VERSION 5.8 ;
BUSBITCHARS "[]" ;
DIVIDERCHAR "/" ;
UNITS
    DATABASE MICRONS 1000 ;
END UNITS

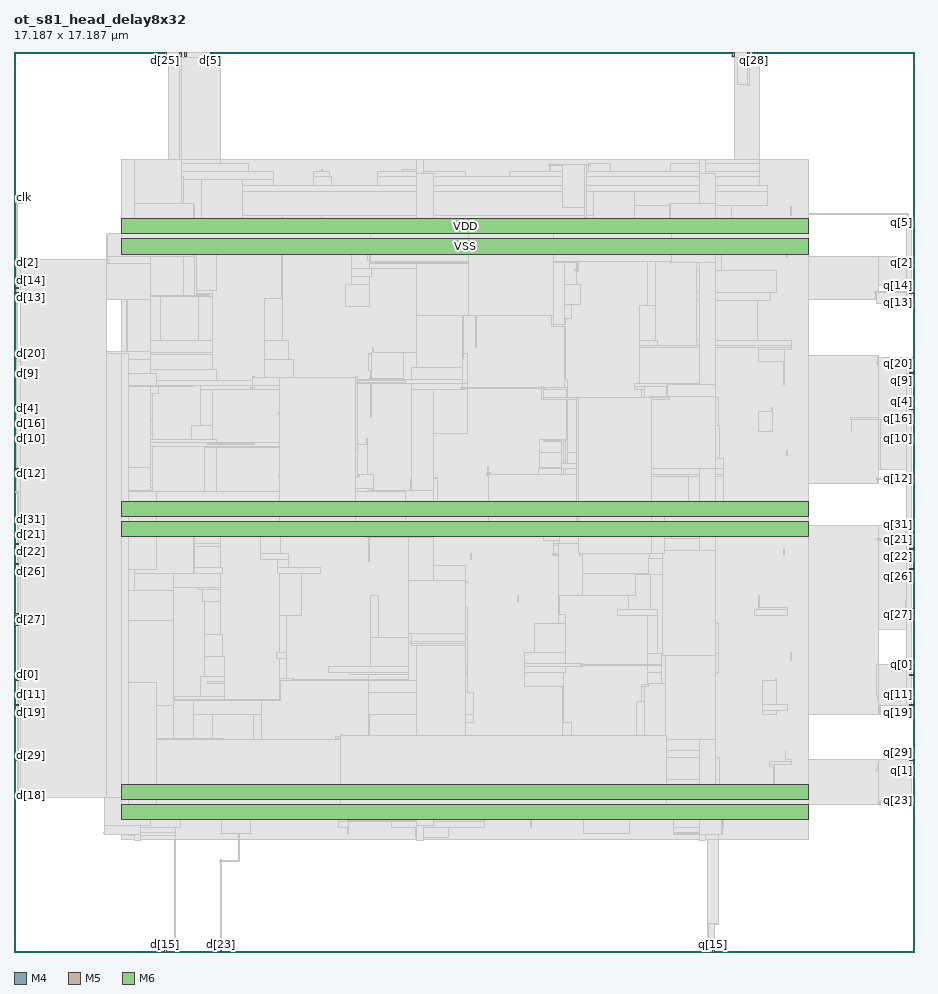
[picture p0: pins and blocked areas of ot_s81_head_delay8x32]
MACRO ot_s81_head_delay8x32
  FOREIGN ot_s81_head_delay8x32 0 0 ;
  CLASS BLOCK ;
  SIZE 17.187 BY 17.187 ;
  PIN clk
    DIRECTION INPUT ;
    USE SIGNAL ;
    PORT
      LAYER M4 ;
        RECT  0 14.4 0.084 14.424 ;
    END
  END clk
  PIN d[0]
    DIRECTION INPUT ;
    USE SIGNAL ;
    PORT
      LAYER M4 ;
        RECT  0 5.28 0.084 5.304 ;
    END
  END d[0]
  PIN d[10]
    DIRECTION INPUT ;
    USE SIGNAL ;
    PORT
      LAYER M4 ;
        RECT  0 9.792 0.084 9.816 ;
    END
  END d[10]
  PIN d[11]
    DIRECTION INPUT ;
    USE SIGNAL ;
    PORT
      LAYER M4 ;
        RECT  0 4.896 0.084 4.92 ;
    END
  END d[11]
  PIN d[12]
    DIRECTION INPUT ;
    USE SIGNAL ;
    PORT
      LAYER M4 ;
        RECT  0 9.12 0.084 9.144 ;
    END
  END d[12]
  PIN d[13]
    DIRECTION INPUT ;
    USE SIGNAL ;
    PORT
      LAYER M4 ;
        RECT  0 12.48 0.084 12.504 ;
    END
  END d[13]
  PIN d[14]
    DIRECTION INPUT ;
    USE SIGNAL ;
    PORT
      LAYER M4 ;
        RECT  0 12.672 0.084 12.696 ;
    END
  END d[14]
  PIN d[15]
    DIRECTION INPUT ;
    USE SIGNAL ;
    PORT
      LAYER M5 ;
        RECT  2.88 0 2.904 0.084 ;
    END
  END d[15]
  PIN d[16]
    DIRECTION INPUT ;
    USE SIGNAL ;
    PORT
      LAYER M4 ;
        RECT  0 10.08 0.084 10.104 ;
    END
  END d[16]
  PIN d[17]
    DIRECTION INPUT ;
    USE SIGNAL ;
    PORT
      LAYER M4 ;
        RECT  0 5.184 0.084 5.208 ;
    END
  END d[17]
  PIN d[18]
    DIRECTION INPUT ;
    USE SIGNAL ;
    PORT
      LAYER M4 ;
        RECT  0 2.976 0.084 3 ;
    END
  END d[18]
  PIN d[19]
    DIRECTION INPUT ;
    USE SIGNAL ;
    PORT
      LAYER M4 ;
        RECT  0 4.704 0.084 4.728 ;
    END
  END d[19]
  PIN d[1]
    DIRECTION INPUT ;
    USE SIGNAL ;
    PORT
      LAYER M4 ;
        RECT  0 3.648 0.084 3.672 ;
    END
  END d[1]
  PIN d[20]
    DIRECTION INPUT ;
    USE SIGNAL ;
    PORT
      LAYER M4 ;
        RECT  0 11.424 0.084 11.448 ;
    END
  END d[20]
  PIN d[21]
    DIRECTION INPUT ;
    USE SIGNAL ;
    PORT
      LAYER M4 ;
        RECT  0 7.968 0.084 7.992 ;
    END
  END d[21]
  PIN d[22]
    DIRECTION INPUT ;
    USE SIGNAL ;
    PORT
      LAYER M4 ;
        RECT  0 7.776 0.084 7.8 ;
    END
  END d[22]
  PIN d[23]
    DIRECTION INPUT ;
    USE SIGNAL ;
    PORT
      LAYER M5 ;
        RECT  3.936 0 3.96 0.084 ;
    END
  END d[23]
  PIN d[24]
    DIRECTION INPUT ;
    USE SIGNAL ;
    PORT
      LAYER M4 ;
        RECT  0 11.328 0.084 11.352 ;
    END
  END d[24]
  PIN d[25]
    DIRECTION INPUT ;
    USE SIGNAL ;
    PORT
      LAYER M5 ;
        RECT  2.88 17.103 2.904 17.187 ;
    END
  END d[25]
  PIN d[26]
    DIRECTION INPUT ;
    USE SIGNAL ;
    PORT
      LAYER M4 ;
        RECT  0 7.392 0.084 7.416 ;
    END
  END d[26]
  PIN d[27]
    DIRECTION INPUT ;
    USE SIGNAL ;
    PORT
      LAYER M4 ;
        RECT  0 6.336 0.084 6.36 ;
    END
  END d[27]
  PIN d[28]
    DIRECTION INPUT ;
    USE SIGNAL ;
    PORT
      LAYER M5 ;
        RECT  3.264 17.103 3.288 17.187 ;
    END
  END d[28]
  PIN d[29]
    DIRECTION INPUT ;
    USE SIGNAL ;
    PORT
      LAYER M4 ;
        RECT  0 3.744 0.084 3.768 ;
    END
  END d[29]
  PIN d[2]
    DIRECTION INPUT ;
    USE SIGNAL ;
    PORT
      LAYER M4 ;
        RECT  0 13.152 0.084 13.176 ;
    END
  END d[2]
  PIN d[30]
    DIRECTION INPUT ;
    USE SIGNAL ;
    PORT
      LAYER M5 ;
        RECT  3.168 17.103 3.192 17.187 ;
    END
  END d[30]
  PIN d[31]
    DIRECTION INPUT ;
    USE SIGNAL ;
    PORT
      LAYER M4 ;
        RECT  0 8.256 0.084 8.28 ;
    END
  END d[31]
  PIN d[3]
    DIRECTION INPUT ;
    USE SIGNAL ;
    PORT
      LAYER M4 ;
        RECT  0 6.432 0.084 6.456 ;
    END
  END d[3]
  PIN d[4]
    DIRECTION INPUT ;
    USE SIGNAL ;
    PORT
      LAYER M4 ;
        RECT  0 10.368 0.084 10.392 ;
    END
  END d[4]
  PIN d[5]
    DIRECTION INPUT ;
    USE SIGNAL ;
    PORT
      LAYER M5 ;
        RECT  3.744 17.103 3.768 17.187 ;
    END
  END d[5]
  PIN d[6]
    DIRECTION INPUT ;
    USE SIGNAL ;
    PORT
      LAYER M4 ;
        RECT  0 12.576 0.084 12.6 ;
    END
  END d[6]
  PIN d[7]
    DIRECTION INPUT ;
    USE SIGNAL ;
    PORT
      LAYER M4 ;
        RECT  0 9.216 0.084 9.24 ;
    END
  END d[7]
  PIN d[8]
    DIRECTION INPUT ;
    USE SIGNAL ;
    PORT
      LAYER M4 ;
        RECT  0 6.24 0.084 6.264 ;
    END
  END d[8]
  PIN d[9]
    DIRECTION INPUT ;
    USE SIGNAL ;
    PORT
      LAYER M4 ;
        RECT  0 11.04 0.084 11.064 ;
    END
  END d[9]
  PIN q[0]
    DIRECTION OUTPUT ;
    USE SIGNAL ;
    PORT
      LAYER M4 ;
        RECT  17.103 5.472 17.187 5.496 ;
    END
  END q[0]
  PIN q[10]
    DIRECTION OUTPUT ;
    USE SIGNAL ;
    PORT
      LAYER M4 ;
        RECT  17.103 9.792 17.187 9.816 ;
    END
  END q[10]
  PIN q[11]
    DIRECTION OUTPUT ;
    USE SIGNAL ;
    PORT
      LAYER M4 ;
        RECT  17.103 4.896 17.187 4.92 ;
    END
  END q[11]
  PIN q[12]
    DIRECTION OUTPUT ;
    USE SIGNAL ;
    PORT
      LAYER M4 ;
        RECT  17.103 9.024 17.187 9.048 ;
    END
  END q[12]
  PIN q[13]
    DIRECTION OUTPUT ;
    USE SIGNAL ;
    PORT
      LAYER M4 ;
        RECT  17.103 12.384 17.187 12.408 ;
    END
  END q[13]
  PIN q[14]
    DIRECTION OUTPUT ;
    USE SIGNAL ;
    PORT
      LAYER M4 ;
        RECT  17.103 12.576 17.187 12.6 ;
    END
  END q[14]
  PIN q[15]
    DIRECTION OUTPUT ;
    USE SIGNAL ;
    PORT
      LAYER M5 ;
        RECT  13.344 0 13.368 0.084 ;
    END
  END q[15]
  PIN q[16]
    DIRECTION OUTPUT ;
    USE SIGNAL ;
    PORT
      LAYER M4 ;
        RECT  17.103 10.176 17.187 10.2 ;
    END
  END q[16]
  PIN q[17]
    DIRECTION OUTPUT ;
    USE SIGNAL ;
    PORT
      LAYER M4 ;
        RECT  17.103 5.28 17.187 5.304 ;
    END
  END q[17]
  PIN q[18]
    DIRECTION OUTPUT ;
    USE SIGNAL ;
    PORT
      LAYER M5 ;
        RECT  13.248 0 13.272 0.084 ;
    END
  END q[18]
  PIN q[19]
    DIRECTION OUTPUT ;
    USE SIGNAL ;
    PORT
      LAYER M4 ;
        RECT  17.103 4.704 17.187 4.728 ;
    END
  END q[19]
  PIN q[1]
    DIRECTION OUTPUT ;
    USE SIGNAL ;
    PORT
      LAYER M4 ;
        RECT  17.103 3.456 17.187 3.48 ;
    END
  END q[1]
  PIN q[20]
    DIRECTION OUTPUT ;
    USE SIGNAL ;
    PORT
      LAYER M4 ;
        RECT  17.103 11.232 17.187 11.256 ;
    END
  END q[20]
  PIN q[21]
    DIRECTION OUTPUT ;
    USE SIGNAL ;
    PORT
      LAYER M4 ;
        RECT  17.103 7.872 17.187 7.896 ;
    END
  END q[21]
  PIN q[22]
    DIRECTION OUTPUT ;
    USE SIGNAL ;
    PORT
      LAYER M4 ;
        RECT  17.103 7.68 17.187 7.704 ;
    END
  END q[22]
  PIN q[23]
    DIRECTION OUTPUT ;
    USE SIGNAL ;
    PORT
      LAYER M4 ;
        RECT  17.103 2.88 17.187 2.904 ;
    END
  END q[23]
  PIN q[24]
    DIRECTION OUTPUT ;
    USE SIGNAL ;
    PORT
      LAYER M4 ;
        RECT  17.103 11.328 17.187 11.352 ;
    END
  END q[24]
  PIN q[25]
    DIRECTION OUTPUT ;
    USE SIGNAL ;
    PORT
      LAYER M5 ;
        RECT  13.728 17.103 13.752 17.187 ;
    END
  END q[25]
  PIN q[26]
    DIRECTION OUTPUT ;
    USE SIGNAL ;
    PORT
      LAYER M4 ;
        RECT  17.103 7.296 17.187 7.32 ;
    END
  END q[26]
  PIN q[27]
    DIRECTION OUTPUT ;
    USE SIGNAL ;
    PORT
      LAYER M4 ;
        RECT  17.103 6.432 17.187 6.456 ;
    END
  END q[27]
  PIN q[28]
    DIRECTION OUTPUT ;
    USE SIGNAL ;
    PORT
      LAYER M5 ;
        RECT  14.112 17.103 14.136 17.187 ;
    END
  END q[28]
  PIN q[29]
    DIRECTION OUTPUT ;
    USE SIGNAL ;
    PORT
      LAYER M4 ;
        RECT  17.103 3.648 17.187 3.672 ;
    END
  END q[29]
  PIN q[2]
    DIRECTION OUTPUT ;
    USE SIGNAL ;
    PORT
      LAYER M4 ;
        RECT  17.103 13.152 17.187 13.176 ;
    END
  END q[2]
  PIN q[30]
    DIRECTION OUTPUT ;
    USE SIGNAL ;
    PORT
      LAYER M5 ;
        RECT  14.016 17.103 14.04 17.187 ;
    END
  END q[30]
  PIN q[31]
    DIRECTION OUTPUT ;
    USE SIGNAL ;
    PORT
      LAYER M4 ;
        RECT  17.103 8.16 17.187 8.184 ;
    END
  END q[31]
  PIN q[3]
    DIRECTION OUTPUT ;
    USE SIGNAL ;
    PORT
      LAYER M4 ;
        RECT  17.103 6.528 17.187 6.552 ;
    END
  END q[3]
  PIN q[4]
    DIRECTION OUTPUT ;
    USE SIGNAL ;
    PORT
      LAYER M4 ;
        RECT  17.103 10.368 17.187 10.392 ;
    END
  END q[4]
  PIN q[5]
    DIRECTION OUTPUT ;
    USE SIGNAL ;
    PORT
      LAYER M4 ;
        RECT  17.103 13.92 17.187 13.944 ;
    END
  END q[5]
  PIN q[6]
    DIRECTION OUTPUT ;
    USE SIGNAL ;
    PORT
      LAYER M4 ;
        RECT  17.103 12.48 17.187 12.504 ;
    END
  END q[6]
  PIN q[7]
    DIRECTION OUTPUT ;
    USE SIGNAL ;
    PORT
      LAYER M4 ;
        RECT  17.103 9.12 17.187 9.144 ;
    END
  END q[7]
  PIN q[8]
    DIRECTION OUTPUT ;
    USE SIGNAL ;
    PORT
      LAYER M4 ;
        RECT  17.103 6.336 17.187 6.36 ;
    END
  END q[8]
  PIN q[9]
    DIRECTION OUTPUT ;
    USE SIGNAL ;
    PORT
      LAYER M4 ;
        RECT  17.103 11.04 17.187 11.064 ;
    END
  END q[9]
  PIN VDD
    DIRECTION INOUT ;
    USE POWER ;
    PORT
      LAYER M6 ;
        RECT  2.052 13.713 15.174 14.001 ;
        RECT  2.052 8.313 15.174 8.601 ;
        RECT  2.052 2.913 15.174 3.201 ;
    END
  END VDD
  PIN VSS
    DIRECTION INOUT ;
    USE GROUND ;
    PORT
      LAYER M6 ;
        RECT  2.052 13.329 15.174 13.617 ;
        RECT  2.052 7.929 15.174 8.217 ;
        RECT  2.052 2.529 15.174 2.817 ;
    END
  END VSS
  OBS
    LAYER RVTN ;
     RECT  2.052 2.16 15.174 2.295 ;
     RECT  2.052 2.565 15.174 2.835 ;
     RECT  2.052 3.105 15.174 3.375 ;
     RECT  2.052 3.645 15.174 3.915 ;
     RECT  2.052 4.185 15.174 4.455 ;
     RECT  2.052 4.725 15.174 4.995 ;
     RECT  2.052 5.265 15.174 5.535 ;
     RECT  2.052 5.805 15.174 6.075 ;
     RECT  2.052 6.345 15.174 6.615 ;
     RECT  2.052 6.885 15.174 7.155 ;
     RECT  2.052 7.425 15.174 7.695 ;
     RECT  2.052 7.965 15.174 8.235 ;
     RECT  2.052 8.505 15.174 8.775 ;
     RECT  2.052 9.045 15.174 9.315 ;
     RECT  2.052 9.585 15.174 9.855 ;
     RECT  2.052 10.125 15.174 10.395 ;
     RECT  2.052 10.665 15.174 10.935 ;
     RECT  2.052 11.205 15.174 11.475 ;
     RECT  2.052 11.745 15.174 12.015 ;
     RECT  2.052 12.285 15.174 12.555 ;
     RECT  2.052 12.825 15.174 13.095 ;
     RECT  2.052 13.365 15.174 13.635 ;
     RECT  2.052 13.905 15.174 14.175 ;
     RECT  2.052 14.445 15.174 14.715 ;
     RECT  2.052 14.985 15.174 15.12 ;
    LAYER RVTP ;
     RECT  2.052 2.295 15.174 2.565 ;
     RECT  2.052 2.835 15.174 3.105 ;
     RECT  2.052 3.375 15.174 3.645 ;
     RECT  2.052 3.915 15.174 4.185 ;
     RECT  2.052 4.455 15.174 4.725 ;
     RECT  2.052 4.995 15.174 5.265 ;
     RECT  2.052 5.535 15.174 5.805 ;
     RECT  2.052 6.075 15.174 6.345 ;
     RECT  2.052 6.615 15.174 6.885 ;
     RECT  2.052 7.155 15.174 7.425 ;
     RECT  2.052 7.695 15.174 7.965 ;
     RECT  2.052 8.235 15.174 8.505 ;
     RECT  2.052 8.775 15.174 9.045 ;
     RECT  2.052 9.315 15.174 9.585 ;
     RECT  2.052 9.855 15.174 10.125 ;
     RECT  2.052 10.395 15.174 10.665 ;
     RECT  2.052 10.935 15.174 11.205 ;
     RECT  2.052 11.475 15.174 11.745 ;
     RECT  2.052 12.015 15.174 12.285 ;
     RECT  2.052 12.555 15.174 12.825 ;
     RECT  2.052 13.095 15.174 13.365 ;
     RECT  2.052 13.635 15.174 13.905 ;
     RECT  2.052 14.175 15.174 14.445 ;
     RECT  2.052 14.715 15.174 14.985 ;
    LAYER M1 ;
     RECT  2.052 2.151 15.174 15.129 ;
    LAYER M2 ;
     RECT  1.147 8.172 1.687 8.19 ;
     RECT  1.687 5.85 2.052 5.868 ;
     RECT  1.687 7.74 2.052 8.19 ;
     RECT  1.147 9.792 2.052 9.81 ;
     RECT  1.759 11.412 2.052 11.43 ;
     RECT  1.147 13.032 2.052 13.05 ;
     RECT  2.052 2.151 15.174 15.129 ;
     RECT  15.174 2.808 16.511 3.672 ;
     RECT  15.174 4.536 16.511 8.154 ;
     RECT  15.174 8.946 16.511 11.394 ;
     RECT  15.174 12.456 16.511 13.284 ;
     RECT  16.511 2.808 16.547 2.826 ;
     RECT  16.511 3.654 16.547 3.672 ;
     RECT  16.511 4.536 16.547 5.184 ;
     RECT  16.511 9.216 16.547 11.304 ;
     RECT  16.511 6.156 17.087 8.154 ;
     RECT  16.547 9.216 17.087 10.314 ;
     RECT  16.511 12.726 17.087 13.284 ;
     RECT  15.174 14.076 17.087 14.094 ;
    LAYER M3 ;
     RECT  13.248 0.091 13.266 0.523 ;
     RECT  3.06 0.091 3.078 2.143 ;
     RECT  13.248 0.523 13.446 2.143 ;
     RECT  7.707 2.143 7.797 2.191 ;
     RECT  2.307 2.143 3.078 2.227 ;
     RECT  13.107 2.143 13.446 2.251 ;
     RECT  4.284 1.723 4.302 2.263 ;
     RECT  2.196 2.227 3.078 2.285 ;
     RECT  2.307 2.285 3.078 2.371 ;
     RECT  6.372 2.263 6.39 2.371 ;
     RECT  7.668 2.191 8.298 2.371 ;
     RECT  12.6 2.251 13.446 2.371 ;
     RECT  6.192 2.371 6.39 2.491 ;
     RECT  7.2 2.371 8.982 2.491 ;
     RECT  2.307 2.371 3.186 2.641 ;
     RECT  3.96 2.263 4.518 2.641 ;
     RECT  5.292 2.605 5.31 2.641 ;
     RECT  6.192 2.491 8.982 2.641 ;
     RECT  10.872 2.263 11.754 2.641 ;
     RECT  12.6 2.371 13.554 2.641 ;
     RECT  2.307 2.641 8.982 2.731 ;
     RECT  9.864 2.371 9.882 2.731 ;
     RECT  2.307 2.731 9.882 2.759 ;
     RECT  14.688 2.731 14.706 2.795 ;
     RECT  10.656 2.641 13.554 2.909 ;
     RECT  16.524 2.803 16.542 2.909 ;
     RECT  10.656 2.909 10.674 2.911 ;
     RECT  11.484 2.909 13.554 2.911 ;
     RECT  2.307 2.759 6.894 3.029 ;
     RECT  7.668 2.759 9.378 3.029 ;
     RECT  10.188 2.911 10.674 3.029 ;
     RECT  11.484 2.911 13.662 3.029 ;
     RECT  7.707 3.029 9.234 3.065 ;
     RECT  6.732 3.029 6.786 3.173 ;
     RECT  2.307 3.029 5.814 3.299 ;
     RECT  11.484 3.029 13.482 3.299 ;
     RECT  2.307 3.299 5.634 3.307 ;
     RECT  2.196 3.307 5.634 3.437 ;
     RECT  14.508 2.911 14.526 3.541 ;
     RECT  16.488 3.451 16.506 3.569 ;
     RECT  14.436 3.541 14.526 3.577 ;
     RECT  14.436 3.577 14.85 3.641 ;
     RECT  14.724 3.641 14.85 3.677 ;
     RECT  16.524 3.643 16.542 3.683 ;
     RECT  11.556 3.299 13.482 3.713 ;
     RECT  2.268 3.437 5.634 3.773 ;
     RECT  4.572 3.773 5.634 3.839 ;
     RECT  11.556 3.713 13.389 3.839 ;
     RECT  14.724 3.677 14.742 3.839 ;
     RECT  5.616 3.839 5.634 3.911 ;
     RECT  2.268 3.773 3.798 4.019 ;
     RECT  6.768 3.173 6.786 4.075 ;
     RECT  10.476 3.029 10.638 4.075 ;
     RECT  6.192 4.075 6.786 4.115 ;
     RECT  10.116 4.075 10.638 4.115 ;
     RECT  11.88 3.839 13.389 4.115 ;
     RECT  2.268 4.019 2.682 4.225 ;
     RECT  10.476 4.115 10.638 4.379 ;
     RECT  7.707 3.065 8.622 4.387 ;
     RECT  3.42 4.019 3.798 4.531 ;
     RECT  4.572 3.839 4.734 4.531 ;
     RECT  6.768 4.115 6.786 4.531 ;
     RECT  7.707 4.387 8.766 4.531 ;
     RECT  2.196 4.225 2.682 4.541 ;
     RECT  14.292 4.531 14.562 4.621 ;
     RECT  2.268 4.541 2.682 4.685 ;
     RECT  14.292 4.621 14.778 4.721 ;
     RECT  11.88 4.115 12.042 4.793 ;
     RECT  2.304 4.685 2.682 4.801 ;
     RECT  3.42 4.531 4.734 4.801 ;
     RECT  16.524 4.531 16.542 4.801 ;
     RECT  2.304 4.801 5.094 4.829 ;
     RECT  2.304 4.829 4.014 4.877 ;
     RECT  6.768 4.531 8.766 4.955 ;
     RECT  10.476 4.379 10.494 5.071 ;
     RECT  11.988 4.793 12.042 5.071 ;
     RECT  11.988 5.071 12.114 5.099 ;
     RECT  12.096 5.099 12.114 5.131 ;
     RECT  13.032 4.115 13.389 5.131 ;
     RECT  5.076 4.829 5.094 5.179 ;
     RECT  14.292 4.721 14.562 5.189 ;
     RECT  5.076 5.179 5.346 5.225 ;
     RECT  14.544 5.189 14.562 5.225 ;
     RECT  3.564 4.877 4.014 5.261 ;
     RECT  6.768 4.955 8.658 5.305 ;
     RECT  16.488 4.801 16.542 5.309 ;
     RECT  6.408 5.305 8.658 5.341 ;
     RECT  9.756 5.071 10.494 5.341 ;
     RECT  12.096 5.131 13.389 5.341 ;
     RECT  6.012 5.341 8.658 5.459 ;
     RECT  9.756 5.341 10.53 5.461 ;
     RECT  9.756 5.461 10.854 5.501 ;
     RECT  16.488 5.309 16.506 5.501 ;
     RECT  5.076 5.225 5.202 5.611 ;
     RECT  3.636 5.261 4.014 5.639 ;
     RECT  12.096 5.341 13.446 5.693 ;
     RECT  2.304 4.877 2.79 5.729 ;
     RECT  5.004 5.611 5.202 5.729 ;
     RECT  9.756 5.501 10.53 5.729 ;
     RECT  14.832 5.575 14.85 5.729 ;
     RECT  2.304 5.729 2.646 5.845 ;
     RECT  6.804 5.459 8.658 5.999 ;
     RECT  3.636 5.639 3.978 6.071 ;
     RECT  1.692 5.845 2.646 6.269 ;
     RECT  9.936 5.729 10.53 6.269 ;
     RECT  13.104 5.693 13.446 6.269 ;
     RECT  5.076 5.729 5.202 6.421 ;
     RECT  12.096 5.693 12.294 6.421 ;
     RECT  13.104 6.269 13.389 6.421 ;
     RECT  10.404 6.269 10.53 6.449 ;
     RECT  17.064 6.151 17.082 6.523 ;
     RECT  11.52 6.421 12.294 6.539 ;
     RECT  13.068 6.421 13.389 6.539 ;
     RECT  14.148 6.421 14.778 6.539 ;
     RECT  7.707 5.999 8.658 6.575 ;
     RECT  14.22 6.539 14.778 6.575 ;
     RECT  3.636 6.071 3.942 6.691 ;
     RECT  17.028 6.523 17.082 6.719 ;
     RECT  6.804 5.999 6.966 6.809 ;
     RECT  9.612 6.691 9.63 6.809 ;
     RECT  14.22 6.575 14.238 6.809 ;
     RECT  3.6 6.691 3.942 6.925 ;
     RECT  2.196 6.269 2.646 6.961 ;
     RECT  3.528 6.925 3.942 6.961 ;
     RECT  10.404 6.449 10.422 7.195 ;
     RECT  11.736 6.539 12.15 7.229 ;
     RECT  2.196 6.961 3.942 7.231 ;
     RECT  5.076 6.421 5.49 7.231 ;
     RECT  2.196 7.231 3.978 7.349 ;
     RECT  5.04 7.231 5.85 7.349 ;
     RECT  7.707 6.575 8.622 7.385 ;
     RECT  12.132 7.229 12.15 7.435 ;
     RECT  13.107 6.539 13.389 7.435 ;
     RECT  5.04 7.349 5.238 7.501 ;
     RECT  10.404 7.195 10.818 7.579 ;
     RECT  4.716 7.501 5.238 7.619 ;
     RECT  8.712 7.501 8.73 7.619 ;
     RECT  14.688 7.591 14.706 7.691 ;
     RECT  2.196 7.349 3.942 7.735 ;
     RECT  10.296 7.579 10.818 7.765 ;
     RECT  1.692 7.735 3.942 7.805 ;
     RECT  10.296 7.765 10.854 7.805 ;
     RECT  10.296 7.805 10.422 7.861 ;
     RECT  17.064 6.719 17.082 7.861 ;
     RECT  12.132 7.435 13.389 7.889 ;
     RECT  16.488 7.861 17.082 7.901 ;
     RECT  6.768 7.465 6.786 7.949 ;
     RECT  4.716 7.619 5.094 7.963 ;
     RECT  12.564 7.889 13.389 7.963 ;
     RECT  10.116 7.861 10.422 8.159 ;
     RECT  17.064 7.901 17.082 8.189 ;
     RECT  1.152 7.963 1.17 8.195 ;
     RECT  12.564 7.963 13.446 8.195 ;
     RECT  12.888 8.195 13.446 8.311 ;
     RECT  2.307 7.805 3.942 8.429 ;
     RECT  4.68 7.963 5.094 8.429 ;
     RECT  6.048 8.311 6.066 8.429 ;
     RECT  12.888 8.311 13.59 8.429 ;
     RECT  8.928 8.005 8.946 8.465 ;
     RECT  11.808 8.167 11.826 8.465 ;
     RECT  7.707 7.385 7.989 8.522 ;
     RECT  6.84 8.522 7.989 8.539 ;
     RECT  2.307 8.429 2.862 8.699 ;
     RECT  6.84 8.539 8.082 8.699 ;
     RECT  2.307 8.699 2.754 8.735 ;
     RECT  2.307 8.735 2.646 8.743 ;
     RECT  2.232 8.743 2.646 8.815 ;
     RECT  6.84 8.699 6.858 8.851 ;
     RECT  2.196 8.815 2.646 8.861 ;
     RECT  2.232 8.861 2.646 9.005 ;
     RECT  7.707 8.699 8.082 9.053 ;
     RECT  16.488 8.941 16.506 9.053 ;
     RECT  10.404 8.159 10.422 9.067 ;
     RECT  10.404 9.067 10.53 9.085 ;
     RECT  11.988 8.851 12.114 9.085 ;
     RECT  12.888 8.429 13.554 9.085 ;
     RECT  5.112 9.067 5.13 9.113 ;
     RECT  6.516 8.851 6.858 9.113 ;
     RECT  11.988 9.085 13.554 9.113 ;
     RECT  10.008 9.085 10.53 9.239 ;
     RECT  12.024 9.113 13.554 9.239 ;
     RECT  10.044 9.239 10.53 9.247 ;
     RECT  9.036 9.085 9.054 9.275 ;
     RECT  12.924 9.239 13.554 9.419 ;
     RECT  10.044 9.247 10.746 9.545 ;
     RECT  14.76 9.481 14.778 9.581 ;
     RECT  3.636 8.429 3.87 9.625 ;
     RECT  5.076 9.391 5.094 9.625 ;
     RECT  2.307 9.005 2.646 9.661 ;
     RECT  3.636 9.625 5.094 9.661 ;
     RECT  6.516 9.113 6.75 9.689 ;
     RECT  2.307 9.661 5.094 9.725 ;
     RECT  2.307 9.725 3.87 9.779 ;
     RECT  10.044 9.545 10.566 9.779 ;
     RECT  6.732 9.689 6.75 9.815 ;
     RECT  1.152 9.787 1.17 9.824 ;
     RECT  2.307 9.779 2.646 9.895 ;
     RECT  7.707 9.053 7.989 9.895 ;
     RECT  12.024 9.239 12.186 9.965 ;
     RECT  3.384 9.779 3.798 10.049 ;
     RECT  12.924 9.419 13.482 10.049 ;
     RECT  2.304 9.895 2.646 10.165 ;
     RECT  5.076 9.725 5.094 10.201 ;
     RECT  15.984 9.931 16.002 10.205 ;
     RECT  14.22 9.931 14.49 10.319 ;
     RECT  14.472 10.319 14.49 10.391 ;
     RECT  17.064 9.115 17.082 10.397 ;
     RECT  12.024 9.965 12.042 10.471 ;
     RECT  12.924 10.049 13.446 10.589 ;
     RECT  2.196 10.165 2.646 10.669 ;
     RECT  3.564 10.049 3.798 10.741 ;
     RECT  5.076 10.201 5.166 10.741 ;
     RECT  7.707 9.895 8.658 10.741 ;
     RECT  10.548 9.779 10.566 10.741 ;
     RECT  11.988 10.471 12.042 10.741 ;
     RECT  10.116 10.741 10.566 10.781 ;
     RECT  11.844 10.741 12.042 10.795 ;
     RECT  12.924 10.589 13.389 10.795 ;
     RECT  2.196 10.669 2.754 10.831 ;
     RECT  3.564 10.741 5.346 10.831 ;
     RECT  2.196 10.831 5.346 10.859 ;
     RECT  7.668 10.741 8.658 10.859 ;
     RECT  11.844 10.795 13.389 10.859 ;
     RECT  10.512 10.781 10.566 10.931 ;
     RECT  6.804 10.201 6.822 11.101 ;
     RECT  2.196 10.859 3.87 11.129 ;
     RECT  16.524 11.011 16.542 11.227 ;
     RECT  14.688 10.831 14.706 11.281 ;
     RECT  4.788 10.859 5.346 11.309 ;
     RECT  16.488 11.227 16.542 11.357 ;
     RECT  16.488 11.357 16.506 11.399 ;
     RECT  2.196 11.129 3.798 11.407 ;
     RECT  6.768 11.101 6.822 11.407 ;
     RECT  6.768 11.407 6.93 11.435 ;
     RECT  7.707 10.859 8.658 11.435 ;
     RECT  1.764 11.407 3.798 11.453 ;
     RECT  6.84 11.435 6.93 11.453 ;
     RECT  14.22 11.281 14.706 11.515 ;
     RECT  6.84 11.453 6.858 11.543 ;
     RECT  11.952 10.859 13.389 11.551 ;
     RECT  14.22 11.515 14.85 11.551 ;
     RECT  11.952 11.551 14.85 11.579 ;
     RECT  2.232 11.453 3.798 11.669 ;
     RECT  4.788 11.309 5.238 11.669 ;
     RECT  11.952 11.579 12.294 11.669 ;
     RECT  13.032 11.579 14.85 11.669 ;
     RECT  10.512 10.931 10.53 11.947 ;
     RECT  10.44 11.947 10.53 11.984 ;
     RECT  10.512 11.984 10.53 12.091 ;
     RECT  7.707 11.435 8.082 12.187 ;
     RECT  8.82 11.551 8.838 12.187 ;
     RECT  7.707 12.187 8.838 12.325 ;
     RECT  11.952 11.669 12.258 12.353 ;
     RECT  10.512 12.091 10.638 12.361 ;
     RECT  13.032 11.669 14.202 12.451 ;
     RECT  16.488 12.379 16.506 12.475 ;
     RECT  16.488 12.475 17.082 12.478 ;
     RECT  4.788 11.669 5.13 12.479 ;
     RECT  7.707 12.325 8.91 12.479 ;
     RECT  2.232 11.669 2.79 12.523 ;
     RECT  3.528 11.669 3.798 12.523 ;
     RECT  2.232 12.523 3.798 12.571 ;
     RECT  13.032 12.451 14.454 12.595 ;
     RECT  16.452 12.478 17.082 12.605 ;
     RECT  2.196 12.571 3.798 12.631 ;
     RECT  6.336 12.325 6.786 12.749 ;
     RECT  10.512 12.361 10.818 12.749 ;
     RECT  6.444 12.749 6.786 12.901 ;
     RECT  13.032 12.595 14.562 13.019 ;
     RECT  6.444 12.901 6.822 13.051 ;
     RECT  1.152 12.571 1.17 13.055 ;
     RECT  10.512 12.749 10.746 13.171 ;
     RECT  7.707 12.479 8.694 13.333 ;
     RECT  14.76 13.261 14.778 13.361 ;
     RECT  7.707 13.333 8.946 13.405 ;
     RECT  2.196 12.631 3.87 13.441 ;
     RECT  5.112 12.479 5.13 13.441 ;
     RECT  12.096 12.353 12.258 13.441 ;
     RECT  13.032 13.019 13.518 13.441 ;
     RECT  2.196 13.441 5.13 13.559 ;
     RECT  6.444 13.051 6.966 13.639 ;
     RECT  6.264 13.639 6.966 13.711 ;
     RECT  9.936 13.171 10.746 13.711 ;
     RECT  6.012 13.711 6.966 13.819 ;
     RECT  2.196 13.559 3.582 13.865 ;
     RECT  5.868 13.819 6.966 13.963 ;
     RECT  7.707 13.405 9.126 13.963 ;
     RECT  12.096 13.441 13.518 13.963 ;
     RECT  5.868 13.963 9.126 13.981 ;
     RECT  9.936 13.711 10.998 13.981 ;
     RECT  11.988 13.963 13.518 13.981 ;
     RECT  4.356 13.559 5.13 14.071 ;
     RECT  5.868 13.981 11.07 14.071 ;
     RECT  17.064 12.605 17.082 14.099 ;
     RECT  14.832 14.071 14.85 14.243 ;
     RECT  11.844 13.981 13.698 14.251 ;
     RECT  4.356 14.071 11.07 14.521 ;
     RECT  11.844 14.251 14.382 14.521 ;
     RECT  4.356 14.521 14.382 14.639 ;
     RECT  2.307 13.865 3.582 14.755 ;
     RECT  4.356 14.639 4.95 14.755 ;
     RECT  5.724 14.639 6.066 14.819 ;
     RECT  6.948 14.639 14.238 14.819 ;
     RECT  2.307 14.755 4.95 14.909 ;
     RECT  5.724 14.819 6.03 14.909 ;
     RECT  6.948 14.819 8.622 14.909 ;
     RECT  9.468 14.819 14.238 14.909 ;
     RECT  5.868 14.909 5.886 14.945 ;
     RECT  7.416 14.909 7.797 14.945 ;
     RECT  2.307 14.909 4.482 15.053 ;
     RECT  10.224 14.909 10.242 15.053 ;
     RECT  10.98 14.909 11.394 15.053 ;
     RECT  12.528 14.909 14.238 15.053 ;
     RECT  10.98 15.053 10.998 15.059 ;
     RECT  2.307 15.053 3.942 15.137 ;
     RECT  7.707 14.945 7.797 15.137 ;
     RECT  13.107 15.053 14.238 15.137 ;
     RECT  2.952 15.137 3.942 17.117 ;
     RECT  13.752 15.137 14.238 17.117 ;
    LAYER M4 ;
     RECT  0.037 14.304 0.06 14.328 ;
     RECT  0.06 2.976 0.131 11.448 ;
     RECT  0.131 3.744 0.179 3.768 ;
     RECT  0.131 9.12 0.179 11.448 ;
     RECT  0.06 12.48 0.179 13.176 ;
     RECT  0.06 14.304 0.179 14.424 ;
     RECT  0.131 6.24 0.227 6.456 ;
     RECT  0.179 11.328 0.227 11.352 ;
     RECT  0.179 9.12 0.275 9.816 ;
     RECT  0.275 9.216 0.323 9.816 ;
     RECT  0.131 4.896 0.563 4.92 ;
     RECT  0.323 9.792 1.181 9.816 ;
     RECT  0.227 6.24 1.717 6.264 ;
     RECT  0.131 7.776 1.717 7.992 ;
     RECT  0.179 12.576 1.717 12.6 ;
     RECT  1.717 12.576 1.765 13.128 ;
     RECT  1.717 3.408 2.149 3.432 ;
     RECT  1.717 4.512 2.149 4.536 ;
     RECT  1.717 6.24 2.149 8.856 ;
     RECT  1.709 11.424 2.149 11.448 ;
     RECT  1.765 12.576 2.149 13.704 ;
     RECT  1.717 2.256 2.3 2.28 ;
     RECT  2.149 3.36 2.3 3.432 ;
     RECT  2.149 4.512 2.3 13.704 ;
     RECT  2.3 2.148 2.404 15.132 ;
     RECT  2.404 2.418 2.596 14.862 ;
     RECT  2.596 7.2 2.723 7.992 ;
     RECT  2.596 10.848 2.723 10.968 ;
     RECT  2.596 4.512 2.737 4.872 ;
     RECT  2.737 4.848 3.059 4.872 ;
     RECT  2.869 0.096 3.089 0.12 ;
     RECT  2.596 12.528 3.241 14.808 ;
     RECT  2.723 7.248 3.443 7.992 ;
     RECT  2.723 10.848 3.443 10.872 ;
     RECT  3.241 12.528 3.443 14.28 ;
     RECT  3.443 12.528 3.484 13.32 ;
     RECT  3.484 12.528 3.737 12.552 ;
     RECT  3.443 7.968 3.769 7.992 ;
     RECT  2.869 17.088 3.953 17.112 ;
     RECT  2.596 2.88 3.973 3.384 ;
     RECT  3.697 5.136 4.025 5.16 ;
     RECT  3.973 2.88 4.028 3.768 ;
     RECT  4.028 2.832 4.061 3.768 ;
     RECT  4.061 2.832 4.115 3.384 ;
     RECT  3.925 1.728 4.313 1.752 ;
     RECT  4.115 3.36 4.601 3.384 ;
     RECT  3.697 9.696 4.601 9.72 ;
     RECT  4.517 10.752 4.601 10.776 ;
     RECT  3.769 7.968 4.709 8.04 ;
     RECT  4.561 13.68 5.101 13.704 ;
     RECT  4.709 8.016 5.105 8.04 ;
     RECT  5.057 9.072 5.141 9.096 ;
     RECT  5.057 10.272 5.141 10.296 ;
     RECT  5.101 13.68 6.037 13.848 ;
     RECT  6.133 4.08 6.285 4.104 ;
     RECT  6.469 9.648 6.505 9.672 ;
     RECT  6.505 9.072 6.556 9.672 ;
     RECT  6.556 9.072 6.589 9.096 ;
     RECT  6.716 7.92 6.757 7.944 ;
     RECT  6.037 13.68 6.757 13.992 ;
     RECT  6.757 13.2 6.793 13.992 ;
     RECT  6.793 10.944 6.829 10.968 ;
     RECT  6.829 10.944 7.429 11.448 ;
     RECT  5.317 5.184 7.525 5.208 ;
     RECT  6.757 7.92 7.573 8.808 ;
     RECT  6.361 2.496 7.7 2.52 ;
     RECT  7.525 5.184 7.7 6.12 ;
     RECT  7.573 7.92 7.7 9.048 ;
     RECT  7.429 10.896 7.7 11.448 ;
     RECT  6.793 13.056 7.7 13.992 ;
     RECT  7.7 2.148 7.804 15.132 ;
     RECT  7.804 2.418 7.996 14.862 ;
     RECT  7.996 10.944 8.021 12.216 ;
     RECT  7.996 8.544 8.093 9.048 ;
     RECT  8.021 11.328 8.579 12.216 ;
     RECT  7.996 4.608 8.627 4.632 ;
     RECT  7.996 5.712 8.627 5.736 ;
     RECT  7.996 3.408 8.633 3.432 ;
     RECT  7.996 7.056 8.668 7.08 ;
     RECT  8.579 12.192 8.723 12.216 ;
     RECT  7.996 13.488 8.963 13.512 ;
     RECT  9.025 9.12 9.109 9.144 ;
     RECT  10.069 10.752 10.156 10.776 ;
     RECT  10.076 4.08 10.163 4.104 ;
     RECT  10.285 7.584 10.393 7.608 ;
     RECT  10.105 9.744 10.453 9.768 ;
     RECT  10.213 15.024 10.465 15.048 ;
     RECT  10.261 11.952 10.469 11.976 ;
     RECT  9.205 3.024 10.541 3.048 ;
     RECT  10.453 9.072 10.541 9.768 ;
     RECT  10.541 9.264 10.577 9.768 ;
     RECT  10.577 9.264 10.787 9.288 ;
     RECT  10.7 13.008 10.787 13.032 ;
     RECT  10.393 6.816 10.865 7.8 ;
     RECT  10.465 14.208 10.897 15.048 ;
     RECT  10.897 13.968 10.937 15.048 ;
     RECT  10.937 15.024 11.009 15.048 ;
     RECT  11.221 2.88 11.581 2.904 ;
     RECT  11.581 2.88 11.621 3.432 ;
     RECT  10.865 6.816 11.873 7.224 ;
     RECT  11.621 3.408 12.017 3.432 ;
     RECT  11.873 7.2 12.121 7.224 ;
     RECT  10.825 5.472 12.373 5.496 ;
     RECT  12.133 9.264 12.469 9.96 ;
     RECT  10.937 13.968 12.517 13.992 ;
     RECT  12.517 13.968 12.553 14.28 ;
     RECT  12.589 2.256 13.1 2.28 ;
     RECT  12.421 4.08 13.1 4.104 ;
     RECT  12.373 5.136 13.1 5.688 ;
     RECT  12.121 7.2 13.1 7.512 ;
     RECT  12.469 9.264 13.1 10.824 ;
     RECT  12.553 13.584 13.1 14.28 ;
     RECT  13.1 2.148 13.204 15.132 ;
     RECT  13.237 0.096 13.379 0.552 ;
     RECT  13.204 2.256 13.396 14.862 ;
     RECT  13.379 0.528 13.457 0.552 ;
     RECT  13.396 7.968 13.457 7.992 ;
     RECT  13.396 2.256 13.523 2.904 ;
     RECT  13.523 2.88 13.537 2.904 ;
     RECT  13.697 17.088 13.813 17.112 ;
     RECT  13.813 16.56 14.051 17.112 ;
     RECT  14.051 17.088 14.249 17.112 ;
     RECT  16.441 12.576 16.477 12.6 ;
     RECT  16.477 3.456 16.513 3.48 ;
     RECT  16.477 4.896 16.513 5.496 ;
     RECT  15.973 10.176 16.513 10.2 ;
     RECT  16.477 11.232 16.513 11.256 ;
     RECT  16.513 4.704 17.053 5.496 ;
     RECT  17.017 6.528 17.053 6.552 ;
     RECT  16.477 7.872 17.053 7.896 ;
     RECT  16.477 9.024 17.053 9.048 ;
     RECT  16.513 10.176 17.053 11.352 ;
     RECT  16.477 12.384 17.053 12.6 ;
     RECT  16.513 2.88 17.148 3.672 ;
     RECT  17.053 4.704 17.148 11.352 ;
     RECT  17.053 12.384 17.148 13.944 ;
    LAYER M5 ;
     RECT  2.88 0.016 2.904 0.131 ;
     RECT  13.248 0.016 13.368 0.131 ;
     RECT  13.248 0.131 13.272 0.563 ;
     RECT  3.936 0.016 3.96 1.763 ;
     RECT  2.292 2.137 2.412 2.245 ;
     RECT  13.092 2.137 13.212 2.245 ;
     RECT  1.728 2.245 2.412 2.407 ;
     RECT  7.692 2.137 7.812 2.407 ;
     RECT  13.092 2.245 13.512 2.915 ;
     RECT  4.08 2.821 4.104 3.395 ;
     RECT  0.096 2.933 0.12 3.445 ;
     RECT  0.096 3.445 0.168 3.683 ;
     RECT  0.144 3.683 0.168 3.779 ;
     RECT  1.728 2.407 2.604 4.021 ;
     RECT  3.984 3.733 4.008 4.021 ;
     RECT  13.092 2.915 13.404 4.051 ;
     RECT  6.144 4.021 6.168 4.069 ;
     RECT  1.728 4.021 4.008 4.075 ;
     RECT  7.692 2.407 8.004 4.085 ;
     RECT  6.144 4.069 6.264 4.115 ;
     RECT  10.128 4.051 10.152 4.139 ;
     RECT  6.24 4.115 6.264 4.153 ;
     RECT  1.728 4.075 3.048 4.715 ;
     RECT  0.096 4.661 0.12 4.885 ;
     RECT  0.096 4.885 0.552 5.035 ;
     RECT  12.432 4.051 13.404 5.653 ;
     RECT  7.692 4.085 8.616 5.845 ;
     RECT  7.584 5.845 8.616 6.085 ;
     RECT  2.16 4.715 3.048 6.325 ;
     RECT  0.096 5.035 0.12 6.421 ;
     RECT  0.096 6.421 0.216 6.507 ;
     RECT  1.728 6.325 3.048 6.899 ;
     RECT  7.536 6.085 8.616 7.091 ;
     RECT  2.292 6.899 3.048 7.237 ;
     RECT  10.8 7.573 10.824 7.659 ;
     RECT  12.384 5.653 13.404 7.659 ;
     RECT  7.536 7.091 8.004 7.909 ;
     RECT  2.292 7.237 3.432 7.957 ;
     RECT  1.92 7.957 3.432 8.003 ;
     RECT  0.096 6.507 0.12 8.757 ;
     RECT  6.768 7.909 8.004 8.819 ;
     RECT  1.92 8.003 2.604 8.821 ;
     RECT  0.048 8.757 0.12 9.109 ;
     RECT  9.072 9.071 9.096 9.155 ;
     RECT  0.048 9.109 0.264 9.171 ;
     RECT  10.464 9.043 10.488 9.235 ;
     RECT  13.092 7.659 13.404 9.235 ;
     RECT  0.048 9.171 0.312 9.259 ;
     RECT  1.728 8.821 2.604 9.259 ;
     RECT  10.464 9.235 10.776 9.323 ;
     RECT  6.528 9.061 6.552 9.619 ;
     RECT  6.48 9.619 6.552 9.707 ;
     RECT  10.464 9.323 10.488 9.779 ;
     RECT  5.088 9.061 5.112 10.307 ;
     RECT  12.144 9.235 13.404 10.603 ;
     RECT  7.584 8.819 8.004 10.741 ;
     RECT  10.08 10.549 10.104 10.795 ;
     RECT  2.16 9.259 2.604 10.805 ;
     RECT  12.48 10.603 13.404 10.835 ;
     RECT  6.528 9.707 6.552 10.847 ;
     RECT  7.584 10.741 8.568 10.847 ;
     RECT  2.16 10.805 3.432 10.893 ;
     RECT  2.16 10.893 3.336 10.923 ;
     RECT  6.528 10.847 8.568 10.931 ;
     RECT  4.56 10.741 4.584 10.987 ;
     RECT  6.528 10.931 6.552 10.987 ;
     RECT  2.16 10.923 2.712 11.051 ;
     RECT  7.584 10.931 8.568 11.171 ;
     RECT  0.048 9.259 0.168 11.283 ;
     RECT  2.16 11.051 2.604 11.317 ;
     RECT  0.048 11.283 0.216 11.382 ;
     RECT  1.728 11.317 2.604 11.459 ;
     RECT  0.048 11.382 0.168 11.469 ;
     RECT  7.692 11.171 8.568 12.149 ;
     RECT  10.272 11.941 10.296 12.203 ;
     RECT  0.048 11.469 0.072 12.435 ;
     RECT  2.16 11.459 2.604 12.469 ;
     RECT  1.728 12.469 2.604 13.139 ;
     RECT  7.692 12.149 8.712 13.151 ;
     RECT  6.816 13.151 8.712 13.173 ;
     RECT  13.092 10.835 13.404 13.173 ;
     RECT  0.048 12.435 0.168 13.227 ;
     RECT  10.752 12.997 10.776 13.227 ;
     RECT  6.816 13.173 8.952 13.235 ;
     RECT  1.776 13.139 2.604 13.285 ;
     RECT  7.692 13.235 8.952 13.523 ;
     RECT  1.776 13.285 3.432 13.715 ;
     RECT  2.292 13.715 3.432 14.291 ;
     RECT  12.528 13.173 13.404 14.291 ;
     RECT  0.048 13.227 0.072 14.293 ;
     RECT  0.048 14.293 0.168 14.339 ;
     RECT  0.144 14.339 0.168 14.435 ;
     RECT  7.692 13.523 8.004 14.873 ;
     RECT  13.092 14.291 13.404 14.873 ;
     RECT  2.292 14.291 3.192 15.143 ;
     RECT  7.692 14.873 7.812 15.143 ;
     RECT  13.092 14.873 13.212 15.143 ;
     RECT  3.168 15.143 3.192 17.077 ;
     RECT  14.016 16.549 14.04 17.077 ;
     RECT  2.88 17.077 3.768 17.168 ;
     RECT  13.728 17.077 14.136 17.168 ;
    LAYER M6 ;
     RECT  0.037 8.768 0.085 8.8 ;
     RECT  0.085 2.944 0.133 8.8 ;
     RECT  0.133 2.944 1.763 13.216 ;
     RECT  1.763 13.184 1.811 13.216 ;
     RECT  1.763 2.944 2.052 11.424 ;
     RECT  2.052 2.529 2.195 11.424 ;
     RECT  2.195 2.529 2.723 5.152 ;
     RECT  2.195 7.296 2.723 8.8 ;
     RECT  2.195 10.816 2.723 11.04 ;
     RECT  2.723 10.816 4.549 10.912 ;
     RECT  2.723 7.929 5.077 8.8 ;
     RECT  4.549 10.816 5.077 10.976 ;
     RECT  2.723 2.529 6.229 4.064 ;
     RECT  5.077 7.929 6.515 10.976 ;
     RECT  6.515 10.88 6.563 10.976 ;
     RECT  2.052 13.329 6.805 14.001 ;
     RECT  6.515 7.929 7.475 8.8 ;
     RECT  6.563 10.88 7.475 10.912 ;
     RECT  7.573 5.888 8.627 5.92 ;
     RECT  6.805 13.184 8.677 14.001 ;
     RECT  7.475 7.929 9.061 8.601 ;
     RECT  8.533 10.752 10.069 10.784 ;
     RECT  10.069 10.56 10.115 10.784 ;
     RECT  8.677 12.16 10.307 14.001 ;
     RECT  9.061 7.929 10.741 9.12 ;
     RECT  10.115 10.56 10.741 10.592 ;
     RECT  10.741 7.929 10.789 10.592 ;
     RECT  10.789 7.616 12.179 10.592 ;
     RECT  12.179 7.616 12.419 8.601 ;
     RECT  6.229 2.529 12.467 4.128 ;
     RECT  12.179 10.56 12.515 10.592 ;
     RECT  10.307 13.184 12.563 14.001 ;
     RECT  12.467 2.529 15.174 3.201 ;
     RECT  12.419 7.929 15.174 8.601 ;
     RECT  12.563 13.329 15.174 14.001 ;
  END
END ot_s81_head_delay8x32
END LIBRARY
